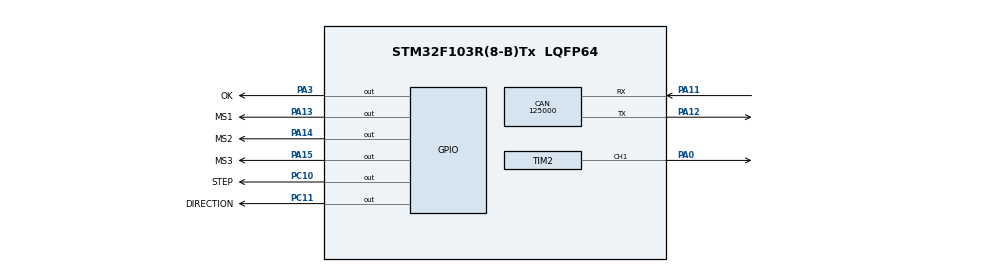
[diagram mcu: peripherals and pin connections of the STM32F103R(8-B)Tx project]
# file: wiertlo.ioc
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CAN.BS1=CAN_BS1_2TQ
CAN.CalculateBaudRate=125000
CAN.CalculateTimeBit=8000
CAN.CalculateTimeQuantum=2000.0
Mcu.Family=STM32F1
Mcu.Name=STM32F103R(8-B)Tx
Mcu.Package=LQFP64
NVIC.PriorityGroup=NVIC_PRIORITYGROUP_4
NVIC.TIM2_IRQn=true\:10\:0\:true\:false\:true\:true\:true\:true
PA0-WKUP.Signal=S_TIM2_CH1_ETR
PA11.Mode=CAN_Activate
PA11.Signal=CAN_RX
PA12.Mode=CAN_Activate
PA12.Signal=CAN_TX
PA13.GPIO_Label=MS1
PA13.Signal=GPIO_Output
PA14.GPIO_Label=MS2
PA14.Signal=GPIO_Output
PA15.GPIO_Label=MS3
PA15.Signal=GPIO_Output
PA3.GPIO_Label=OK
PA3.PinState=GPIO_PIN_SET
PA3.Signal=GPIO_Output
PC10.GPIO_Label=STEP
PC10.Signal=GPIO_Output
PC11.GPIO_Label=DIRECTION
PC11.Signal=GPIO_Output
ProjectManager.HeapSize=0x200
ProjectManager.StackSize=0x400
ProjectManager.TargetToolchain=STM32CubeIDE
RCC.APB1Freq_Value=8000000
RCC.APB2Freq_Value=8000000
SH.S_TIM2_CH1_ETR.0=TIM2_CH1,PWM Generation1 CH1
TIM2.Channel-PWM\ Generation1\ CH1=TIM_CHANNEL_1
TIM2.Period=999
TIM2.Prescaler=159
TIM2.Pulse-PWM\ Generation1\ CH1=0
VP_TIM2_VS_ClockSourceINT.Mode=Internal
board=custom

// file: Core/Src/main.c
/* USER CODE BEGIN Header */
/**
  ******************************************************************************
  * @file           : main.c
  * @brief          : Main program body
  ******************************************************************************
  * @attention
  *
  * Copyright (c) 2024 STMicroelectronics.
  * All rights reserved.
  *
  * This software is licensed under terms that can be found in the LICENSE file
  * in the root directory of this software component.
  * If no LICENSE file comes with this software, it is provided AS-IS.
  *
  ******************************************************************************
  */
/* USER CODE END Header */
#include "main.h"

/* USER CODE BEGIN Includes */
#include <stdbool.h>
#include "PWM.h"
#include "can.h"
#include "gpio.h"
#include "hx711.h"

/* USER CODE END Includes */

void SystemClock_Config(void);

/* USER CODE BEGIN 0 */

extern CAN_TxHeaderTypeDef   TxHeader;
extern uint8_t               TxData[8];
extern uint32_t              TxMailbox;
extern CAN_RxHeaderTypeDef   RxHeader;
extern uint8_t               RxData[8];
extern int step;
void stepper_resolution();
void one_step();

/* USER CODE END 0 */

int main(void)
{
  /* USER CODE BEGIN 1 */

	TxHeader.IDE = CAN_ID_STD;
	TxHeader.StdId = 194;
	TxHeader.RTR = CAN_RTR_DATA;
	TxHeader.DLC = 2;

	TxData[0] = 50;
	TxData[1] = 0xAA;
  /* USER CODE END 1 */

  /* MCU Configuration--------------------------------------------------------*/

  /* Reset of all peripherals, Initializes the Flash interface and the Systick. */
  HAL_Init();

  /* Configure the system clock */
  SystemClock_Config();

  /* Initialize all configured peripherals */
  MX_GPIO_Init();
  MX_TIM2_Init();
  MX_CAN_Init();
  /* USER CODE BEGIN 2 */
  PWM_START();
  stepper_resolution();

  /* USER CODE END 2 */

  /* Infinite loop */
  /* USER CODE BEGIN WHILE */
  while (1)
  {

	  one_step();
      motor_speed();
    // can_transmit();

    /* USER CODE END WHILE */

  }
}

void SystemClock_Config(void)
{
	RCC_OscInitTypeDef RCC_OscInitStruct = {0};
	  RCC_ClkInitTypeDef RCC_ClkInitStruct = {0};
	  RCC_PeriphCLKInitTypeDef PeriphClkInit = {0};

	  /** Initializes the CPU, AHB and APB busses clocks
	  */
	  RCC_OscInitStruct.OscillatorType = RCC_OSCILLATORTYPE_HSE;
	  RCC_OscInitStruct.HSEState = RCC_HSE_ON;
	  RCC_OscInitStruct.HSEPredivValue = RCC_HSE_PREDIV_DIV1;
	  RCC_OscInitStruct.HSIState = RCC_HSI_ON;
	  RCC_OscInitStruct.PLL.PLLState = RCC_PLL_ON;
	  RCC_OscInitStruct.PLL.PLLSource = RCC_PLLSOURCE_HSE;
	  RCC_OscInitStruct.PLL.PLLMUL = RCC_PLL_MUL9;
	  if (HAL_RCC_OscConfig(&RCC_OscInitStruct) != HAL_OK)
	  {
	    Error_Handler();
	  }
	  /** Initializes the CPU, AHB and APB busses clocks
	  */
	  RCC_ClkInitStruct.ClockType = RCC_CLOCKTYPE_HCLK|RCC_CLOCKTYPE_SYSCLK
	                              |RCC_CLOCKTYPE_PCLK1|RCC_CLOCKTYPE_PCLK2;
	  RCC_ClkInitStruct.SYSCLKSource = RCC_SYSCLKSOURCE_PLLCLK;
	  RCC_ClkInitStruct.AHBCLKDivider = RCC_SYSCLK_DIV1;
	  RCC_ClkInitStruct.APB1CLKDivider = RCC_HCLK_DIV2;
	  RCC_ClkInitStruct.APB2CLKDivider = RCC_HCLK_DIV1;

	  if (HAL_RCC_ClockConfig(&RCC_ClkInitStruct, FLASH_LATENCY_2) != HAL_OK)
	  {
	    Error_Handler();
	  }
	  PeriphClkInit.PeriphClockSelection = RCC_PERIPHCLK_ADC;
	  PeriphClkInit.AdcClockSelection = RCC_ADCPCLK2_DIV6;
	  if (HAL_RCCEx_PeriphCLKConfig(&PeriphClkInit) != HAL_OK)
	  {
	    Error_Handler();
	  }
}

/* USER CODE BEGIN 4 */

void stepper_resolution()
{
	HAL_GPIO_WritePin(MS1_GPIO_Port, MS1_Pin, GPIO_PIN_SET);
	HAL_GPIO_WritePin(MS2_GPIO_Port, MS2_Pin, GPIO_PIN_RESET);
	HAL_GPIO_WritePin(MS3_GPIO_Port, MS3_Pin, GPIO_PIN_RESET);
	HAL_GPIO_WritePin(DIRECTION_GPIO_Port, DIRECTION_Pin, GPIO_PIN_SET);

}

void one_step()
{
if(step==1)
{
	for(int i =0; i<80; i++){
		  HAL_Delay(10);

		  HAL_GPIO_TogglePin(STEP_GPIO_Port, STEP_Pin);
		  }
}
step=0;
}

/* USER CODE END 4 */

void Error_Handler(void)
{
  __disable_irq();
  while (1)
  {
  }
}
